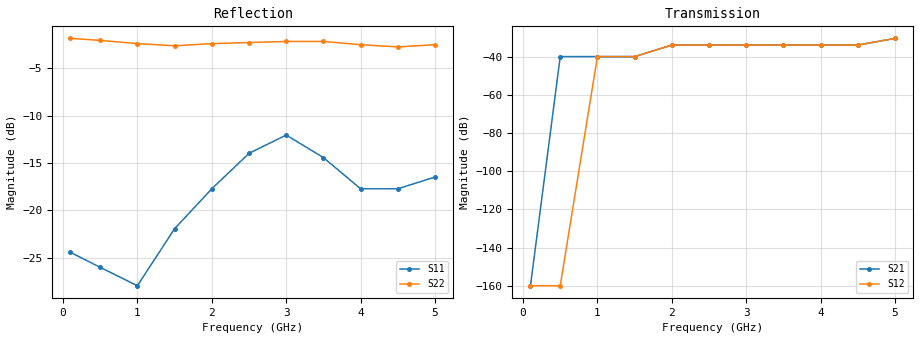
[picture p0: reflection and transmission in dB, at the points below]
!  MGS-70018 S PARAMETERS
!  "off" port  LAST UPDATED 07-22-92
# ghz s ma r 50
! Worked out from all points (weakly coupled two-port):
!   11 points, 100 MHz to 5 GHz, reference 50 ohm
!   highest |S21| = -30.46 dB at 5 GHz (marker M1); lowest = -40.0 dB at 500 MHz (marker M2)
!   lowest |S11| = -28.0 dB at 1 GHz (marker M3), VSWR 1.08, Z = 53.4 - j2.39 ohm
!   |S11| at or under -10 dB: start of sweep to end of sweep
!   |S22| runs from -2.7 to -1.8 dB; largest |S21 - S12| = 0.06
0.1  0.06 -15.0  0 -60.0  0 -78.0  0.81 177.0
0.5  0.05 -55.0  0.01 -15.0  0 -25.0  0.79 167.0
1  0.04 -34.0  0.01 55.0  0.01 51.0  0.76 147.0
1.5  0.08 26.0  0.01 134.0  0.01 138.0  0.74 130.0
2  0.13 28.0  0.02 -140.0  0.02 -134.0  0.76 106.0
2.5  0.2 23.0  0.02 -35.0  0.02 -33.0  0.77 106.0
3  0.25 19.0  0.02 77.0  0.02 68.0  0.78 98.0
3.5  0.19 11.0  0.02 168.0  0.02 170.0  0.78 96.0
4  0.13 -8.0  0.02 -96.0  0.02 -95.0  0.75 90.0
4.5  0.13 15.0  0.02 -7.0  0.02 20.0  0.73 68.0
5  0.15 47.0  0.03 -88.0  0.03 90.0  0.75 39.0
